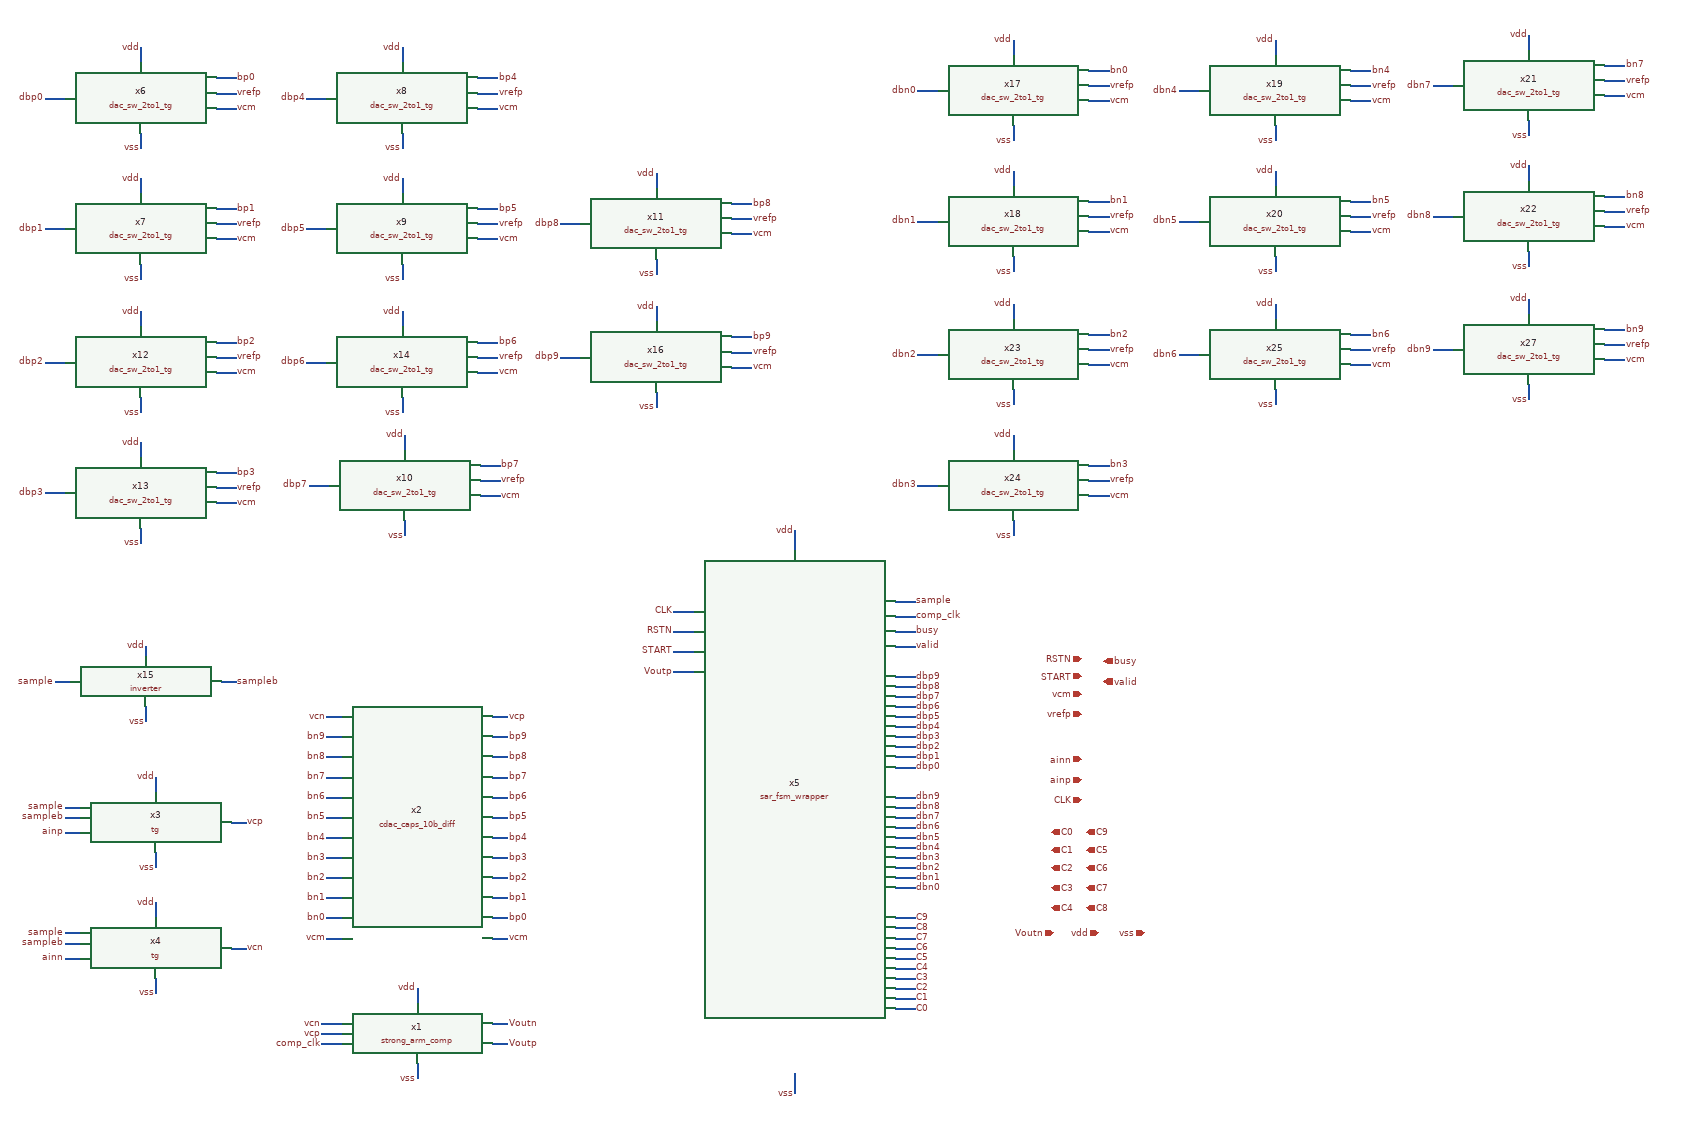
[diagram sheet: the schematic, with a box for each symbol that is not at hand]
v {xschem version=3.4.5 file_version=1.2
}
G {}
K {}
V {}
S {}
E {}
N 820 -270 820 -240 {
lab=vdd}
N 970 -200 1000 -200 {
lab=Voutn}
N 970 -160 1000 -160 {
lab=Voutp}
N 630 -200 670 -200 {
lab=vcn}
N 630 -180 670 -180 {
lab=vcp}
N 630 -160 670 -160 {
lab=comp_clk}
N 820 -120 820 -90 {
lab=vss}
N 300 -690 300 -660 {
lab=vdd}
N 300 -540 300 -510 {
lab=vss}
N 450 -600 480 -600 {
lab=vcp}
N 120 -630 150 -630 {
lab=sample}
N 120 -610 150 -610 {
lab=sampleb}
N 120 -580 150 -580 {
lab=ainp}
N 300 -440 300 -410 {
lab=vdd}
N 300 -290 300 -260 {
lab=vss}
N 450 -350 480 -350 {
lab=vcn}
N 120 -380 150 -380 {
lab=sample}
N 120 -360 150 -360 {
lab=sampleb}
N 120 -330 150 -330 {
lab=ainn}
N 970 -810 1000 -810 {
lab=vcp}
N 970 -770 1000 -770 {
lab=bp9}
N 970 -730 1000 -730 {
lab=bp8}
N 970 -690 1000 -690 {
lab=bp7}
N 970 -650 1000 -650 {
lab=bp6}
N 970 -610 1000 -610 {
lab=bp5}
N 970 -570 1000 -570 {
lab=bp4}
N 970 -530 1000 -530 {
lab=bp3}
N 970 -490 1000 -490 {
lab=bp2}
N 970 -450 1000 -450 {
lab=bp1}
N 970 -410 1000 -410 {
lab=bp0}
N 970 -370 1000 -370 {
lab=vcm}
N 640 -810 670 -810 {
lab=vcn}
N 650 -770 670 -770 {
lab=bn9}
N 640 -770 650 -770 {
lab=bn9}
N 640 -730 670 -730 {
lab=bn8}
N 640 -690 670 -690 {
lab=bn7}
N 640 -650 670 -650 {
lab=bn6}
N 640 -610 670 -610 {
lab=bn5}
N 640 -570 670 -570 {
lab=bn4}
N 640 -530 670 -530 {
lab=bn3}
N 640 -490 670 -490 {
lab=bn2}
N 640 -450 670 -450 {
lab=bn1}
N 640 -410 670 -410 {
lab=bn0}
N 640 -370 670 -370 {
lab=vcm}
N 1330 -1020 1370 -1020 {
lab=CLK}
N 1330 -980 1370 -980 {
lab=RSTN}
N 1330 -940 1370 -940 {
lab=START}
N 1330 -900 1370 -900 {
lab=Voutp}
N 1770 -1040 1810 -1040 {
lab=sample}
N 1770 -1010 1810 -1010 {
lab=comp_clk}
N 1770 -980 1810 -980 {
lab=busy}
N 1770 -950 1810 -950 {
lab=valid}
N 1770 -890 1810 -890 {
lab=dbp9}
N 1770 -870 1810 -870 {
lab=dbp8}
N 1770 -850 1810 -850 {
lab=dbp7}
N 1770 -830 1810 -830 {
lab=dbp6}
N 1770 -810 1810 -810 {
lab=dbp5}
N 1770 -790 1810 -790 {
lab=dbp4}
N 1770 -770 1810 -770 {
lab=dbp3}
N 1770 -750 1810 -750 {
lab=dbp2}
N 1770 -730 1810 -730 {
lab=dbp1}
N 1770 -710 1810 -710 {
lab=dbp0}
N 1770 -650 1810 -650 {
lab=dbn9}
N 1770 -630 1810 -630 {
lab=dbn8}
N 1770 -610 1810 -610 {
lab=dbn7}
N 1770 -590 1810 -590 {
lab=dbn6}
N 1770 -570 1810 -570 {
lab=dbn5}
N 1770 -550 1810 -550 {
lab=dbn4}
N 1770 -530 1810 -530 {
lab=dbn3}
N 1770 -510 1810 -510 {
lab=dbn2}
N 1770 -490 1810 -490 {
lab=dbn1}
N 1770 -470 1810 -470 {
lab=dbn0}
N 1770 -410 1810 -410 {
lab=C9}
N 1770 -390 1810 -390 {
lab=C8}
N 1770 -370 1810 -370 {
lab=C7}
N 1770 -350 1810 -350 {
lab=C6}
N 1770 -330 1810 -330 {
lab=C5}
N 1770 -310 1810 -310 {
lab=C4}
N 1770 -290 1810 -290 {
lab=C3}
N 1770 -270 1810 -270 {
lab=C2}
N 1770 -250 1810 -250 {
lab=C1}
N 1770 -230 1810 -230 {
lab=C0}
N 1570 -1180 1570 -1140 {
lab=vdd}
N 1570 -100 1570 -60 {
lab=vss}
N 100 -880 130 -880 {
lab=sample}
N 280 -950 280 -930 {
lab=vdd}
N 430 -880 460 -880 {
lab=sampleb}
N 280 -830 280 -800 {
lab=vss}
N 270 -2140 270 -2110 {
lab=vdd}
N 80 -2040 120 -2040 {
lab=dbp0}
N 270 -1970 270 -1940 {
lab=vss}
N 420 -2080 460 -2080 {
lab=bp0}
N 420 -2050 460 -2050 {
lab=vrefp}
N 420 -2020 460 -2020 {
lab=vcm}
N 270 -1880 270 -1850 {
lab=vdd}
N 80 -1780 120 -1780 {
lab=dbp1}
N 270 -1710 270 -1680 {
lab=vss}
N 420 -1820 460 -1820 {
lab=bp1}
N 420 -1790 460 -1790 {
lab=vrefp}
N 420 -1760 460 -1760 {
lab=vcm}
N 790 -2140 790 -2110 {
lab=vdd}
N 600 -2040 640 -2040 {
lab=dbp4}
N 790 -1970 790 -1940 {
lab=vss}
N 940 -2080 980 -2080 {
lab=bp4}
N 940 -2050 980 -2050 {
lab=vrefp}
N 940 -2020 980 -2020 {
lab=vcm}
N 790 -1880 790 -1850 {
lab=vdd}
N 600 -1780 640 -1780 {
lab=dbp5}
N 790 -1710 790 -1680 {
lab=vss}
N 940 -1820 980 -1820 {
lab=bp5}
N 940 -1790 980 -1790 {
lab=vrefp}
N 940 -1760 980 -1760 {
lab=vcm}
N 795 -1370 795 -1340 {
lab=vdd}
N 605 -1270 645 -1270 {
lab=dbp7}
N 795 -1200 795 -1170 {
lab=vss}
N 945 -1310 985 -1310 {
lab=bp7}
N 945 -1280 985 -1280 {
lab=vrefp}
N 945 -1250 985 -1250 {
lab=vcm}
N 1295 -1890 1295 -1860 {
lab=vdd}
N 1105 -1790 1145 -1790 {
lab=dbp8}
N 1295 -1720 1295 -1690 {
lab=vss}
N 1445 -1830 1485 -1830 {
lab=bp8}
N 1445 -1800 1485 -1800 {
lab=vrefp}
N 1445 -1770 1485 -1770 {
lab=vcm}
N 270 -1615 270 -1585 {
lab=vdd}
N 80 -1515 120 -1515 {
lab=dbp2}
N 270 -1445 270 -1415 {
lab=vss}
N 420 -1555 460 -1555 {
lab=bp2}
N 420 -1525 460 -1525 {
lab=vrefp}
N 420 -1495 460 -1495 {
lab=vcm}
N 270 -1355 270 -1325 {
lab=vdd}
N 80 -1255 120 -1255 {
lab=dbp3}
N 270 -1185 270 -1155 {
lab=vss}
N 420 -1295 460 -1295 {
lab=bp3}
N 420 -1265 460 -1265 {
lab=vrefp}
N 420 -1235 460 -1235 {
lab=vcm}
N 790 -1615 790 -1585 {
lab=vdd}
N 600 -1515 640 -1515 {
lab=dbp6}
N 790 -1445 790 -1415 {
lab=vss}
N 940 -1555 980 -1555 {
lab=bp6}
N 940 -1525 980 -1525 {
lab=vrefp}
N 940 -1495 980 -1495 {
lab=vcm}
N 1295 -1625 1295 -1595 {
lab=vdd}
N 1105 -1525 1145 -1525 {
lab=dbp9}
N 1295 -1455 1295 -1425 {
lab=vss}
N 1445 -1565 1485 -1565 {
lab=bp9}
N 1445 -1535 1485 -1535 {
lab=vrefp}
N 1445 -1505 1485 -1505 {
lab=vcm}
N 2005 -2155 2005 -2125 {
lab=vdd}
N 1815 -2055 1855 -2055 {
lab=dbn0}
N 2005 -1985 2005 -1955 {
lab=vss}
N 2155 -2095 2195 -2095 {
lab=bn0}
N 2155 -2065 2195 -2065 {
lab=vrefp}
N 2155 -2035 2195 -2035 {
lab=vcm}
N 2005 -1895 2005 -1865 {
lab=vdd}
N 1815 -1795 1855 -1795 {
lab=dbn1}
N 2005 -1725 2005 -1695 {
lab=vss}
N 2155 -1835 2195 -1835 {
lab=bn1}
N 2155 -1805 2195 -1805 {
lab=vrefp}
N 2155 -1775 2195 -1775 {
lab=vcm}
N 2525 -2155 2525 -2125 {
lab=vdd}
N 2335 -2055 2375 -2055 {
lab=dbn4}
N 2525 -1985 2525 -1955 {
lab=vss}
N 2675 -2095 2715 -2095 {
lab=bn4}
N 2675 -2065 2715 -2065 {
lab=vrefp}
N 2675 -2035 2715 -2035 {
lab=vcm}
N 2525 -1895 2525 -1865 {
lab=vdd}
N 2335 -1795 2375 -1795 {
lab=dbn5}
N 2525 -1725 2525 -1695 {
lab=vss}
N 2675 -1835 2715 -1835 {
lab=bn5}
N 2675 -1805 2715 -1805 {
lab=vrefp}
N 2675 -1775 2715 -1775 {
lab=vcm}
N 3030 -2165 3030 -2135 {
lab=vdd}
N 2840 -2065 2880 -2065 {
lab=dbn7}
N 3030 -1995 3030 -1965 {
lab=vss}
N 3180 -2105 3220 -2105 {
lab=bn7}
N 3180 -2075 3220 -2075 {
lab=vrefp}
N 3180 -2045 3220 -2045 {
lab=vcm}
N 3030 -1905 3030 -1875 {
lab=vdd}
N 2840 -1805 2880 -1805 {
lab=dbn8}
N 3030 -1735 3030 -1705 {
lab=vss}
N 3180 -1845 3220 -1845 {
lab=bn8}
N 3180 -1815 3220 -1815 {
lab=vrefp}
N 3180 -1785 3220 -1785 {
lab=vcm}
N 2005 -1630 2005 -1600 {
lab=vdd}
N 1815 -1530 1855 -1530 {
lab=dbn2}
N 2005 -1460 2005 -1430 {
lab=vss}
N 2155 -1570 2195 -1570 {
lab=bn2}
N 2155 -1540 2195 -1540 {
lab=vrefp}
N 2155 -1510 2195 -1510 {
lab=vcm}
N 2005 -1370 2005 -1340 {
lab=vdd}
N 1815 -1270 1855 -1270 {
lab=dbn3}
N 2005 -1200 2005 -1170 {
lab=vss}
N 2155 -1310 2195 -1310 {
lab=bn3}
N 2155 -1280 2195 -1280 {
lab=vrefp}
N 2155 -1250 2195 -1250 {
lab=vcm}
N 2525 -1630 2525 -1600 {
lab=vdd}
N 2335 -1530 2375 -1530 {
lab=dbn6}
N 2525 -1460 2525 -1430 {
lab=vss}
N 2675 -1570 2715 -1570 {
lab=bn6}
N 2675 -1540 2715 -1540 {
lab=vrefp}
N 2675 -1510 2715 -1510 {
lab=vcm}
N 3030 -1640 3030 -1610 {
lab=vdd}
N 2840 -1540 2880 -1540 {
lab=dbn9}
N 3030 -1470 3030 -1440 {
lab=vss}
N 3180 -1580 3220 -1580 {
lab=bn9}
N 3180 -1550 3220 -1550 {
lab=vrefp}
N 3180 -1520 3220 -1520 {
lab=vcm}
C {strong_arm_comp.sym} 820 -180 0 0 {name=x1}
C {lab_pin.sym} 630 -180 0 0 {name=p1 sig_type=std_logic lab=vcp}
C {lab_pin.sym} 630 -200 0 0 {name=p2 sig_type=std_logic lab=vcn}
C {lab_pin.sym} 630 -160 0 0 {name=p3 sig_type=std_logic lab=comp_clk}
C {lab_pin.sym} 1000 -160 2 0 {name=p4 sig_type=std_logic lab=Voutp}
C {lab_pin.sym} 1000 -200 2 0 {name=p5 sig_type=std_logic lab=Voutn}
C {lab_pin.sym} 820 -270 0 0 {name=p6 sig_type=std_logic lab=vdd

}
C {lab_pin.sym} 820 -90 0 0 {name=p7 sig_type=std_logic lab=vss

}
C {lab_pin.sym} 640 -810 0 0 {name=p10 sig_type=std_logic lab=vcn


}
C {lab_pin.sym} 1000 -810 2 0 {name=p11 sig_type=std_logic lab=vcp


}
C {tg.sym} 300 -600 0 0 {name=x3}
C {lab_pin.sym} 300 -690 0 0 {name=p12 sig_type=std_logic lab=vdd

}
C {lab_pin.sym} 300 -510 0 0 {name=p13 sig_type=std_logic lab=vss

}
C {lab_pin.sym} 120 -630 0 0 {name=p14 sig_type=std_logic lab=sample}
C {lab_pin.sym} 120 -610 0 0 {name=p15 sig_type=std_logic lab=sampleb}
C {lab_pin.sym} 120 -580 0 0 {name=p16 sig_type=std_logic lab=ainp}
C {lab_pin.sym} 480 -600 2 0 {name=p18 sig_type=std_logic lab=vcp


}
C {tg.sym} 300 -350 0 0 {name=x4}
C {lab_pin.sym} 300 -440 0 0 {name=p19 sig_type=std_logic lab=vdd

}
C {lab_pin.sym} 300 -260 0 0 {name=p20 sig_type=std_logic lab=vss

}
C {lab_pin.sym} 120 -380 0 0 {name=p21 sig_type=std_logic lab=sample}
C {lab_pin.sym} 120 -360 0 0 {name=p22 sig_type=std_logic lab=sampleb}
C {lab_pin.sym} 120 -330 0 0 {name=p23 sig_type=std_logic lab=ainn}
C {lab_pin.sym} 480 -350 2 0 {name=p33 sig_type=std_logic lab=vcn


}
C {lab_pin.sym} 1000 -770 2 0 {name=p37 sig_type=std_logic lab=bp9


}
C {lab_pin.sym} 640 -770 0 0 {name=p38 sig_type=std_logic lab=bn9


}
C {cdac_caps_10b_diff.sym} 820 -590 0 0 {name=x2}
C {lab_pin.sym} 1000 -730 2 0 {name=p39 sig_type=std_logic lab=bp8


}
C {lab_pin.sym} 1000 -690 2 0 {name=p40 sig_type=std_logic lab=bp7


}
C {lab_pin.sym} 1000 -650 2 0 {name=p41 sig_type=std_logic lab=bp6


}
C {lab_pin.sym} 1000 -610 2 0 {name=p42 sig_type=std_logic lab=bp5


}
C {lab_pin.sym} 1000 -570 2 0 {name=p43 sig_type=std_logic lab=bp4


}
C {lab_pin.sym} 1000 -530 2 0 {name=p44 sig_type=std_logic lab=bp3


}
C {lab_pin.sym} 1000 -490 2 0 {name=p45 sig_type=std_logic lab=bp2


}
C {lab_pin.sym} 1000 -450 2 0 {name=p46 sig_type=std_logic lab=bp1


}
C {lab_pin.sym} 1000 -410 2 0 {name=p47 sig_type=std_logic lab=bp0


}
C {lab_pin.sym} 1000 -370 2 0 {name=p48 sig_type=std_logic lab=vcm


}
C {lab_pin.sym} 640 -730 0 0 {name=p49 sig_type=std_logic lab=bn8


}
C {lab_pin.sym} 640 -690 0 0 {name=p50 sig_type=std_logic lab=bn7


}
C {lab_pin.sym} 640 -650 0 0 {name=p51 sig_type=std_logic lab=bn6


}
C {lab_pin.sym} 640 -610 0 0 {name=p52 sig_type=std_logic lab=bn5


}
C {lab_pin.sym} 640 -570 0 0 {name=p53 sig_type=std_logic lab=bn4


}
C {lab_pin.sym} 640 -530 0 0 {name=p54 sig_type=std_logic lab=bn3


}
C {lab_pin.sym} 640 -490 0 0 {name=p55 sig_type=std_logic lab=bn2


}
C {lab_pin.sym} 640 -450 0 0 {name=p56 sig_type=std_logic lab=bn1


}
C {lab_pin.sym} 640 -410 0 0 {name=p57 sig_type=std_logic lab=bn0


}
C {lab_pin.sym} 640 -370 0 0 {name=p58 sig_type=std_logic lab=vcm


}
C {/media/sf_LNA_chipathon/OCCPSense_Capacitive_Pressure_Sensor/rtl/sar_fsm/sar_fsm_wrapper.sym} 1570 -860 0 0 {name=x5}
C {lab_pin.sym} 1570 -1180 0 0 {name=p35 sig_type=std_logic lab=vdd

}
C {lab_pin.sym} 1570 -60 0 0 {name=p36 sig_type=std_logic lab=vss

}
C {lab_pin.sym} 1330 -1020 0 0 {name=p79 sig_type=std_logic lab=CLK}
C {lab_pin.sym} 1810 -890 2 0 {name=p80 sig_type=std_logic lab=dbp9


}
C {lab_pin.sym} 1810 -870 2 0 {name=p81 sig_type=std_logic lab=dbp8


}
C {lab_pin.sym} 1810 -850 2 0 {name=p82 sig_type=std_logic lab=dbp7


}
C {lab_pin.sym} 1810 -830 2 0 {name=p83 sig_type=std_logic lab=dbp6


}
C {lab_pin.sym} 1810 -810 2 0 {name=p84 sig_type=std_logic lab=dbp5


}
C {lab_pin.sym} 1810 -790 2 0 {name=p85 sig_type=std_logic lab=dbp4


}
C {lab_pin.sym} 1810 -770 2 0 {name=p86 sig_type=std_logic lab=dbp3


}
C {lab_pin.sym} 1810 -750 2 0 {name=p87 sig_type=std_logic lab=dbp2


}
C {lab_pin.sym} 1810 -730 2 0 {name=p88 sig_type=std_logic lab=dbp1


}
C {lab_pin.sym} 1810 -710 2 0 {name=p90 sig_type=std_logic lab=dbp0


}
C {lab_pin.sym} 1810 -650 2 0 {name=p91 sig_type=std_logic lab=dbn9


}
C {lab_pin.sym} 1810 -630 2 0 {name=p92 sig_type=std_logic lab=dbn8


}
C {lab_pin.sym} 1810 -610 2 0 {name=p93 sig_type=std_logic lab=dbn7


}
C {lab_pin.sym} 1810 -590 2 0 {name=p94 sig_type=std_logic lab=dbn6


}
C {lab_pin.sym} 1810 -570 2 0 {name=p95 sig_type=std_logic lab=dbn5


}
C {lab_pin.sym} 1810 -550 2 0 {name=p96 sig_type=std_logic lab=dbn4


}
C {lab_pin.sym} 1810 -530 2 0 {name=p97 sig_type=std_logic lab=dbn3


}
C {lab_pin.sym} 1810 -510 2 0 {name=p98 sig_type=std_logic lab=dbn2


}
C {lab_pin.sym} 1810 -490 2 0 {name=p99 sig_type=std_logic lab=dbn1


}
C {lab_pin.sym} 1810 -470 2 0 {name=p100 sig_type=std_logic lab=dbn0


}
C {lab_pin.sym} 1810 -410 2 0 {name=p89 sig_type=std_logic lab=C9


}
C {lab_pin.sym} 1810 -390 2 0 {name=p101 sig_type=std_logic lab=C8


}
C {lab_pin.sym} 1810 -370 2 0 {name=p102 sig_type=std_logic lab=C7


}
C {lab_pin.sym} 1810 -350 2 0 {name=p103 sig_type=std_logic lab=C6


}
C {lab_pin.sym} 1810 -330 2 0 {name=p104 sig_type=std_logic lab=C5


}
C {lab_pin.sym} 1810 -310 2 0 {name=p105 sig_type=std_logic lab=C4


}
C {lab_pin.sym} 1810 -290 2 0 {name=p106 sig_type=std_logic lab=C3


}
C {lab_pin.sym} 1810 -270 2 0 {name=p107 sig_type=std_logic lab=C2


}
C {lab_pin.sym} 1810 -250 2 0 {name=p108 sig_type=std_logic lab=C1


}
C {lab_pin.sym} 1810 -230 2 0 {name=p109 sig_type=std_logic lab=C0


}
C {lab_pin.sym} 1810 -1010 2 0 {name=p110 sig_type=std_logic lab=comp_clk}
C {lab_pin.sym} 1330 -980 0 0 {name=p111 sig_type=std_logic lab=RSTN}
C {lab_pin.sym} 1330 -940 0 0 {name=p112 sig_type=std_logic lab=START}
C {lab_pin.sym} 1330 -900 0 0 {name=p113 sig_type=std_logic lab=Voutp}
C {lab_pin.sym} 1810 -1040 2 0 {name=p114 sig_type=std_logic lab=sample}
C {lab_pin.sym} 1810 -980 2 0 {name=p115 sig_type=std_logic lab=busy
}
C {lab_pin.sym} 1810 -950 2 0 {name=p116 sig_type=std_logic lab=valid}
C {ipin.sym} 2140 -725 0 0 {name=p117 lab=ainn}
C {ipin.sym} 2140 -685 0 0 {name=p119 lab=ainp}
C {ipin.sym} 2140 -645 0 0 {name=p120 lab=CLK}
C {ipin.sym} 2140 -815 0 0 {name=p122 lab=vrefp}
C {ipin.sym} 2140 -855 0 0 {name=p124 lab=vcm}
C {opin.sym} 2080 -545 0 0 {name=p125 lab=C1}
C {opin.sym} 2080 -510 0 0 {name=p126 lab=C2}
C {opin.sym} 2080 -470 0 0 {name=p127 lab=C3}
C {opin.sym} 2080 -430 0 0 {name=p128 lab=C4}
C {opin.sym} 2150 -545 0 0 {name=p129 lab=C5}
C {opin.sym} 2150 -510 0 0 {name=p130 lab=C6}
C {opin.sym} 2150 -470 0 0 {name=p131 lab=C7}
C {opin.sym} 2150 -430 0 0 {name=p132 lab=C8}
C {opin.sym} 2080 -580 0 0 {name=p133 lab=C0}
C {opin.sym} 2150 -580 0 0 {name=p134 lab=C9}
C {opin.sym} 2185 -920 0 0 {name=p135 lab=busy}
C {opin.sym} 2185 -880 0 0 {name=p136 lab=valid}
C {ipin.sym} 2140 -890 0 0 {name=p137 lab=START}
C {ipin.sym} 2140 -925 0 0 {name=p138 lab=RSTN}
C {iopin.sym} 2085 -380 0 0 {name=p167 lab=Voutn}
C {inverter.sym} 280 -880 0 0 {name=x15}
C {lab_pin.sym} 280 -950 0 0 {name=p170 sig_type=std_logic lab=vdd

}
C {lab_pin.sym} 280 -800 0 0 {name=p171 sig_type=std_logic lab=vss

}
C {lab_pin.sym} 100 -880 0 0 {name=p168 sig_type=std_logic lab=sample}
C {lab_pin.sym} 460 -880 2 0 {name=p169 sig_type=std_logic lab=sampleb}
C {dac_sw_2to1_tg.sym} 270 -2040 0 0 {name=x6}
C {lab_pin.sym} 270 -2140 0 0 {name=p17 sig_type=std_logic lab=vdd

}
C {lab_pin.sym} 270 -1940 0 0 {name=p27 sig_type=std_logic lab=vss

}
C {lab_pin.sym} 80 -2040 0 0 {name=p30 sig_type=std_logic lab=dbp0}
C {lab_pin.sym} 460 -2080 2 0 {name=p31 sig_type=std_logic lab=bp0}
C {lab_pin.sym} 460 -2050 2 0 {name=p32 sig_type=std_logic lab=vrefp}
C {lab_pin.sym} 460 -2020 2 0 {name=p34 sig_type=std_logic lab=vcm}
C {dac_sw_2to1_tg.sym} 270 -1780 0 0 {name=x7}
C {lab_pin.sym} 270 -1880 0 0 {name=p59 sig_type=std_logic lab=vdd

}
C {lab_pin.sym} 270 -1680 0 0 {name=p60 sig_type=std_logic lab=vss

}
C {lab_pin.sym} 80 -1780 0 0 {name=p61 sig_type=std_logic lab=dbp1}
C {lab_pin.sym} 460 -1820 2 0 {name=p62 sig_type=std_logic lab=bp1}
C {lab_pin.sym} 460 -1790 2 0 {name=p63 sig_type=std_logic lab=vrefp}
C {lab_pin.sym} 460 -1760 2 0 {name=p64 sig_type=std_logic lab=vcm}
C {dac_sw_2to1_tg.sym} 790 -2040 0 0 {name=x8}
C {lab_pin.sym} 790 -2140 0 0 {name=p65 sig_type=std_logic lab=vdd

}
C {lab_pin.sym} 790 -1940 0 0 {name=p66 sig_type=std_logic lab=vss

}
C {lab_pin.sym} 600 -2040 0 0 {name=p67 sig_type=std_logic lab=dbp4}
C {lab_pin.sym} 980 -2080 2 0 {name=p68 sig_type=std_logic lab=bp4}
C {lab_pin.sym} 980 -2050 2 0 {name=p69 sig_type=std_logic lab=vrefp}
C {lab_pin.sym} 980 -2020 2 0 {name=p70 sig_type=std_logic lab=vcm}
C {dac_sw_2to1_tg.sym} 790 -1780 0 0 {name=x9}
C {lab_pin.sym} 790 -1880 0 0 {name=p71 sig_type=std_logic lab=vdd

}
C {lab_pin.sym} 790 -1680 0 0 {name=p72 sig_type=std_logic lab=vss

}
C {lab_pin.sym} 600 -1780 0 0 {name=p73 sig_type=std_logic lab=dbp5}
C {lab_pin.sym} 980 -1820 2 0 {name=p74 sig_type=std_logic lab=bp5}
C {lab_pin.sym} 980 -1790 2 0 {name=p75 sig_type=std_logic lab=vrefp}
C {lab_pin.sym} 980 -1760 2 0 {name=p76 sig_type=std_logic lab=vcm}
C {dac_sw_2to1_tg.sym} 795 -1270 0 0 {name=x10}
C {lab_pin.sym} 795 -1370 0 0 {name=p77 sig_type=std_logic lab=vdd

}
C {lab_pin.sym} 795 -1170 0 0 {name=p78 sig_type=std_logic lab=vss

}
C {lab_pin.sym} 605 -1270 0 0 {name=p139 sig_type=std_logic lab=dbp7}
C {lab_pin.sym} 985 -1310 2 0 {name=p140 sig_type=std_logic lab=bp7}
C {lab_pin.sym} 985 -1280 2 0 {name=p141 sig_type=std_logic lab=vrefp}
C {lab_pin.sym} 985 -1250 2 0 {name=p142 sig_type=std_logic lab=vcm}
C {dac_sw_2to1_tg.sym} 1295 -1790 0 0 {name=x11}
C {lab_pin.sym} 1295 -1890 0 0 {name=p143 sig_type=std_logic lab=vdd

}
C {lab_pin.sym} 1295 -1690 0 0 {name=p144 sig_type=std_logic lab=vss

}
C {lab_pin.sym} 1105 -1790 0 0 {name=p145 sig_type=std_logic lab=dbp8}
C {lab_pin.sym} 1485 -1830 2 0 {name=p146 sig_type=std_logic lab=bp8}
C {lab_pin.sym} 1485 -1800 2 0 {name=p147 sig_type=std_logic lab=vrefp}
C {lab_pin.sym} 1485 -1770 2 0 {name=p148 sig_type=std_logic lab=vcm}
C {dac_sw_2to1_tg.sym} 270 -1515 0 0 {name=x12}
C {lab_pin.sym} 270 -1615 0 0 {name=p149 sig_type=std_logic lab=vdd

}
C {lab_pin.sym} 270 -1415 0 0 {name=p150 sig_type=std_logic lab=vss

}
C {lab_pin.sym} 80 -1515 0 0 {name=p151 sig_type=std_logic lab=dbp2}
C {lab_pin.sym} 460 -1555 2 0 {name=p152 sig_type=std_logic lab=bp2}
C {lab_pin.sym} 460 -1525 2 0 {name=p153 sig_type=std_logic lab=vrefp}
C {lab_pin.sym} 460 -1495 2 0 {name=p154 sig_type=std_logic lab=vcm}
C {dac_sw_2to1_tg.sym} 270 -1255 0 0 {name=x13}
C {lab_pin.sym} 270 -1355 0 0 {name=p155 sig_type=std_logic lab=vdd

}
C {lab_pin.sym} 270 -1155 0 0 {name=p156 sig_type=std_logic lab=vss

}
C {lab_pin.sym} 80 -1255 0 0 {name=p157 sig_type=std_logic lab=dbp3}
C {lab_pin.sym} 460 -1295 2 0 {name=p158 sig_type=std_logic lab=bp3}
C {lab_pin.sym} 460 -1265 2 0 {name=p159 sig_type=std_logic lab=vrefp}
C {lab_pin.sym} 460 -1235 2 0 {name=p160 sig_type=std_logic lab=vcm}
C {dac_sw_2to1_tg.sym} 790 -1515 0 0 {name=x14}
C {lab_pin.sym} 790 -1615 0 0 {name=p161 sig_type=std_logic lab=vdd

}
C {lab_pin.sym} 790 -1415 0 0 {name=p162 sig_type=std_logic lab=vss

}
C {lab_pin.sym} 600 -1515 0 0 {name=p163 sig_type=std_logic lab=dbp6}
C {lab_pin.sym} 980 -1555 2 0 {name=p164 sig_type=std_logic lab=bp6}
C {lab_pin.sym} 980 -1525 2 0 {name=p165 sig_type=std_logic lab=vrefp}
C {lab_pin.sym} 980 -1495 2 0 {name=p166 sig_type=std_logic lab=vcm}
C {dac_sw_2to1_tg.sym} 1295 -1525 0 0 {name=x16}
C {lab_pin.sym} 1295 -1625 0 0 {name=p173 sig_type=std_logic lab=vdd

}
C {lab_pin.sym} 1295 -1425 0 0 {name=p174 sig_type=std_logic lab=vss

}
C {lab_pin.sym} 1105 -1525 0 0 {name=p175 sig_type=std_logic lab=dbp9}
C {lab_pin.sym} 1485 -1565 2 0 {name=p176 sig_type=std_logic lab=bp9}
C {lab_pin.sym} 1485 -1535 2 0 {name=p177 sig_type=std_logic lab=vrefp}
C {lab_pin.sym} 1485 -1505 2 0 {name=p178 sig_type=std_logic lab=vcm}
C {dac_sw_2to1_tg.sym} 2005 -2055 0 0 {name=x17}
C {lab_pin.sym} 2005 -2155 0 0 {name=p179 sig_type=std_logic lab=vdd

}
C {lab_pin.sym} 2005 -1955 0 0 {name=p180 sig_type=std_logic lab=vss

}
C {lab_pin.sym} 1815 -2055 0 0 {name=p181 sig_type=std_logic lab=dbn0}
C {lab_pin.sym} 2195 -2095 2 0 {name=p182 sig_type=std_logic lab=bn0}
C {lab_pin.sym} 2195 -2065 2 0 {name=p183 sig_type=std_logic lab=vrefp}
C {lab_pin.sym} 2195 -2035 2 0 {name=p184 sig_type=std_logic lab=vcm}
C {dac_sw_2to1_tg.sym} 2005 -1795 0 0 {name=x18}
C {lab_pin.sym} 2005 -1895 0 0 {name=p185 sig_type=std_logic lab=vdd

}
C {lab_pin.sym} 2005 -1695 0 0 {name=p186 sig_type=std_logic lab=vss

}
C {lab_pin.sym} 1815 -1795 0 0 {name=p187 sig_type=std_logic lab=dbn1}
C {lab_pin.sym} 2195 -1835 2 0 {name=p188 sig_type=std_logic lab=bn1}
C {lab_pin.sym} 2195 -1805 2 0 {name=p189 sig_type=std_logic lab=vrefp}
C {lab_pin.sym} 2195 -1775 2 0 {name=p190 sig_type=std_logic lab=vcm}
C {dac_sw_2to1_tg.sym} 2525 -2055 0 0 {name=x19}
C {lab_pin.sym} 2525 -2155 0 0 {name=p191 sig_type=std_logic lab=vdd

}
C {lab_pin.sym} 2525 -1955 0 0 {name=p192 sig_type=std_logic lab=vss

}
C {lab_pin.sym} 2335 -2055 0 0 {name=p193 sig_type=std_logic lab=dbn4}
C {lab_pin.sym} 2715 -2095 2 0 {name=p194 sig_type=std_logic lab=bn4}
C {lab_pin.sym} 2715 -2065 2 0 {name=p195 sig_type=std_logic lab=vrefp}
C {lab_pin.sym} 2715 -2035 2 0 {name=p196 sig_type=std_logic lab=vcm}
C {dac_sw_2to1_tg.sym} 2525 -1795 0 0 {name=x20}
C {lab_pin.sym} 2525 -1895 0 0 {name=p197 sig_type=std_logic lab=vdd

}
C {lab_pin.sym} 2525 -1695 0 0 {name=p198 sig_type=std_logic lab=vss

}
C {lab_pin.sym} 2335 -1795 0 0 {name=p199 sig_type=std_logic lab=dbn5}
C {lab_pin.sym} 2715 -1835 2 0 {name=p200 sig_type=std_logic lab=bn5}
C {lab_pin.sym} 2715 -1805 2 0 {name=p201 sig_type=std_logic lab=vrefp}
C {lab_pin.sym} 2715 -1775 2 0 {name=p202 sig_type=std_logic lab=vcm}
C {dac_sw_2to1_tg.sym} 3030 -2065 0 0 {name=x21}
C {lab_pin.sym} 3030 -2165 0 0 {name=p203 sig_type=std_logic lab=vdd

}
C {lab_pin.sym} 3030 -1965 0 0 {name=p204 sig_type=std_logic lab=vss

}
C {lab_pin.sym} 2840 -2065 0 0 {name=p205 sig_type=std_logic lab=dbn7}
C {lab_pin.sym} 3220 -2105 2 0 {name=p206 sig_type=std_logic lab=bn7}
C {lab_pin.sym} 3220 -2075 2 0 {name=p207 sig_type=std_logic lab=vrefp}
C {lab_pin.sym} 3220 -2045 2 0 {name=p208 sig_type=std_logic lab=vcm}
C {dac_sw_2to1_tg.sym} 3030 -1805 0 0 {name=x22}
C {lab_pin.sym} 3030 -1905 0 0 {name=p209 sig_type=std_logic lab=vdd

}
C {lab_pin.sym} 3030 -1705 0 0 {name=p210 sig_type=std_logic lab=vss

}
C {lab_pin.sym} 2840 -1805 0 0 {name=p211 sig_type=std_logic lab=dbn8}
C {lab_pin.sym} 3220 -1845 2 0 {name=p212 sig_type=std_logic lab=bn8}
C {lab_pin.sym} 3220 -1815 2 0 {name=p213 sig_type=std_logic lab=vrefp}
C {lab_pin.sym} 3220 -1785 2 0 {name=p214 sig_type=std_logic lab=vcm}
C {dac_sw_2to1_tg.sym} 2005 -1530 0 0 {name=x23}
C {lab_pin.sym} 2005 -1630 0 0 {name=p215 sig_type=std_logic lab=vdd

}
C {lab_pin.sym} 2005 -1430 0 0 {name=p216 sig_type=std_logic lab=vss

}
C {lab_pin.sym} 1815 -1530 0 0 {name=p217 sig_type=std_logic lab=dbn2}
C {lab_pin.sym} 2195 -1570 2 0 {name=p218 sig_type=std_logic lab=bn2}
C {lab_pin.sym} 2195 -1540 2 0 {name=p219 sig_type=std_logic lab=vrefp}
C {lab_pin.sym} 2195 -1510 2 0 {name=p220 sig_type=std_logic lab=vcm}
C {dac_sw_2to1_tg.sym} 2005 -1270 0 0 {name=x24}
C {lab_pin.sym} 2005 -1370 0 0 {name=p221 sig_type=std_logic lab=vdd

}
C {lab_pin.sym} 2005 -1170 0 0 {name=p222 sig_type=std_logic lab=vss

}
C {lab_pin.sym} 1815 -1270 0 0 {name=p223 sig_type=std_logic lab=dbn3}
C {lab_pin.sym} 2195 -1310 2 0 {name=p224 sig_type=std_logic lab=bn3}
C {lab_pin.sym} 2195 -1280 2 0 {name=p225 sig_type=std_logic lab=vrefp}
C {lab_pin.sym} 2195 -1250 2 0 {name=p226 sig_type=std_logic lab=vcm}
C {dac_sw_2to1_tg.sym} 2525 -1530 0 0 {name=x25}
C {lab_pin.sym} 2525 -1630 0 0 {name=p227 sig_type=std_logic lab=vdd

}
C {lab_pin.sym} 2525 -1430 0 0 {name=p228 sig_type=std_logic lab=vss

}
C {lab_pin.sym} 2335 -1530 0 0 {name=p229 sig_type=std_logic lab=dbn6}
C {lab_pin.sym} 2715 -1570 2 0 {name=p230 sig_type=std_logic lab=bn6}
C {lab_pin.sym} 2715 -1540 2 0 {name=p231 sig_type=std_logic lab=vrefp}
C {lab_pin.sym} 2715 -1510 2 0 {name=p232 sig_type=std_logic lab=vcm}
C {dac_sw_2to1_tg.sym} 3030 -1540 0 0 {name=x27}
C {lab_pin.sym} 3030 -1640 0 0 {name=p239 sig_type=std_logic lab=vdd

}
C {lab_pin.sym} 3030 -1440 0 0 {name=p240 sig_type=std_logic lab=vss

}
C {lab_pin.sym} 2840 -1540 0 0 {name=p241 sig_type=std_logic lab=dbn9}
C {lab_pin.sym} 3220 -1580 2 0 {name=p242 sig_type=std_logic lab=bn9}
C {lab_pin.sym} 3220 -1550 2 0 {name=p243 sig_type=std_logic lab=vrefp}
C {lab_pin.sym} 3220 -1520 2 0 {name=p244 sig_type=std_logic lab=vcm}
C {iopin.sym} 2175 -380 0 0 {name=p8 lab=vdd}
C {iopin.sym} 2265 -380 0 0 {name=p9 lab=vss}
C {title.sym} 170 0 0 0 {name=l1 author="Arjun Ananth"}
